! (c) 2009  Infineon Technologies AG, Munich
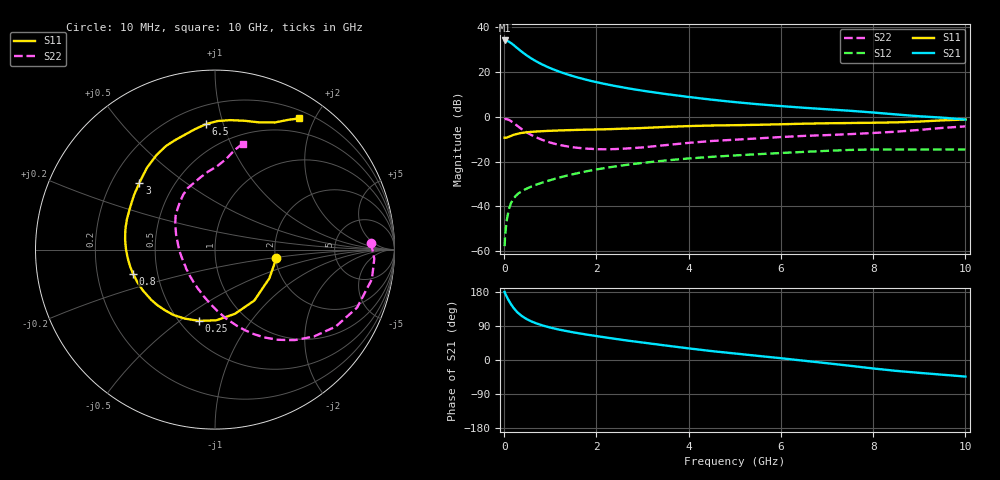
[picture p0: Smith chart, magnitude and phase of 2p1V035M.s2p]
! Infineon Technologies  Discrete & RF Semiconductors
! BFP420
! VCE =  1.0 V,  IC =  35 mA
! Common Emitter S-Parameters:  Nov 2009
# GHz  S  MA  R  50
!  f  S11  S21  S12  S22
! GHz  MAG  ANG  MAG  ANG  MAG  ANG  MAG  ANG
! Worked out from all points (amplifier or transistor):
!   46 points, 10 MHz to 10 GHz, reference 50 ohm
!   highest |S21| = 34.1 dB at 10 MHz (marker M1)
!   |S21| within 3 dB of that: start of sweep to 260.1 MHz
!   unconditionally stable (mu >= 1): start of sweep to 17.36 MHz; 1.282 GHz to end of sweep
!   at 300 MHz: K = 0.47, MSG = 32.4 dB, |S12| = -34.3 dB
!   at 1.7 GHz: K = 1.07, MAG = 19.2 dB, |S12| = -24.7 dB
!   at 10 GHz: K = 1.05, MAG = 5.3 dB, |S12| = -14.5 dB
!   lowest NFmin = 1.64 dB at 900 MHz
!   S11 on the Smith chart (normalised r, x): 10 MHz: 2.00, -0.22; 250 MHz: 0.62, -0.59; 800 MHz: 0.36, -0.13; 3 GHz: 0.32, +0.35; 6.5 GHz: 0.32, +0.88; 10 GHz: 0.30, +1.79
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0.01  0.3414 -8.3  50.42 179.7  0.0013 92.6  0.87 2.4
0.02  0.3411 -12.3  50.02 175.9  0.0021 94.7  0.889 -3.3
0.05  0.3424 -27.8  49.64 168.6  0.0045 85.0  0.8896 -10.7
0.1  0.3585 -52.3  47.58 157.1  0.0086 75.8  0.8551 -22.2
0.15  0.3746 -72.7  44.07 146.9  0.012 70.3  0.7979 -32.5
0.2  0.3939 -88.9  40.26 138.2  0.0148 65.8  0.7336 -41.3
0.25  0.407 -102.6  36.4 130.7  0.0171 62.3  0.6706 -48.8
0.3  0.4197 -113.7  33.04 124.5  0.0192 60.0  0.6118 -55.2
0.35  0.4317 -122.5  30.01 119.3  0.0209 58.4  0.5603 -60.8
0.45  0.4462 -136.2  25.04 110.8  0.0239 56.4  0.4763 -69.9
0.6  0.462 -150.7  19.71 101.3  0.028 55.6  0.3876 -81.0
0.8  0.4757 -163.6  15.12 92.4  0.0333 55.7  0.3129 -92.9
1.2  0.496 179.7  10.12 80.0  0.0442 55.6  0.236 -114.2
1.7  0.5138 165.6  7.047 68.9  0.0583 53.7  0.1985 -137.7
2.2  0.527 154.2  5.356 59.5  0.0724 50.2  0.1883 -158.6
3  0.5624 138.5  3.826 46.1  0.0937 43.1  0.2075 172.5
3.5  0.593 129.7  3.223 38.3  0.106 38.2  0.2332 158.5
5.5  0.6624 104.5  1.907 10.9  0.1465 18.9  0.3293 126.4
6.5  0.7013 94.0  1.589 -1.9  0.1647 9.3  0.3747 113.9
7  0.7164 88.9  1.47 -8.5  0.1741 4.2  0.3904 107.3
8.5  0.751 70.6  1.128 -28.7  0.1858 -13.2  0.465 88.5
10  0.8687 57.3  0.867 -43.7  0.1874 -24.3  0.611 75.3
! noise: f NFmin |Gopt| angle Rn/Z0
0.9  1.64  0.3  -155  0.13
1.8  1.9  0.37  -142  0.15
2.4  2.1  0.34  -134  0.19
3  2.11  0.4  -126  0.22
4  2.25  0.5  -110  0.35
5  2.73  0.54  -94  0.59
6  3.16  0.59  -82  0.84
